VERSION 5.7 ;
BUSBITCHARS "[]" ;
DIVIDERCHAR "/" ;

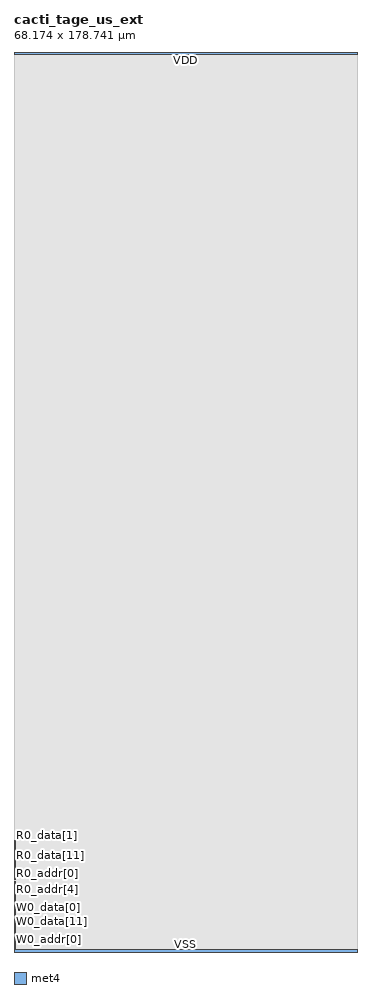
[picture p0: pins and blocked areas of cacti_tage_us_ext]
MACRO cacti_tage_us_ext
  CLASS BLOCK BLACKBOX ;
  ORIGIN 0 0 ;
  FOREIGN cacti_tage_us_ext 0 0 ;
  SIZE 68.174 BY 178.741 ;
  SYMMETRY X Y ;

  PIN VDD
    DIRECTION INOUT ;
    USE POWER ;
    PORT
      LAYER met4 ;
        RECT 0.000 178.241 68.174 178.741 ;
    END
  END VDD
  PIN VSS
    DIRECTION INOUT ;
    USE GROUND ;
    PORT
      LAYER met4 ;
        RECT 0.000 0.000 68.174 0.500 ;
    END
  END VSS
  PIN W0_clk
    DIRECTION INPUT ;
    USE CLOCK ;
    PORT
      LAYER met4 ;
        RECT 0.000 0.700 0.200 0.900 ;
    END
  END W0_clk
  PIN W0_en
    DIRECTION INPUT ;
    USE SIGNAL ;
    PORT
      LAYER met4 ;
        RECT 0.000 1.100 0.200 1.300 ;
    END
  END W0_en
  PIN W0_addr[6]
    DIRECTION INPUT ;
    USE SIGNAL ;
    PORT
      LAYER met4 ;
        RECT 0.000 1.500 0.200 1.700 ;
    END
  END W0_addr[6]
  PIN W0_addr[5]
    DIRECTION INPUT ;
    USE SIGNAL ;
    PORT
      LAYER met4 ;
        RECT 0.000 1.900 0.200 2.100 ;
    END
  END W0_addr[5]
  PIN W0_addr[4]
    DIRECTION INPUT ;
    USE SIGNAL ;
    PORT
      LAYER met4 ;
        RECT 0.000 2.300 0.200 2.500 ;
    END
  END W0_addr[4]
  PIN W0_addr[3]
    DIRECTION INPUT ;
    USE SIGNAL ;
    PORT
      LAYER met4 ;
        RECT 0.000 2.700 0.200 2.900 ;
    END
  END W0_addr[3]
  PIN W0_addr[2]
    DIRECTION INPUT ;
    USE SIGNAL ;
    PORT
      LAYER met4 ;
        RECT 0.000 3.100 0.200 3.300 ;
    END
  END W0_addr[2]
  PIN W0_addr[1]
    DIRECTION INPUT ;
    USE SIGNAL ;
    PORT
      LAYER met4 ;
        RECT 0.000 3.500 0.200 3.700 ;
    END
  END W0_addr[1]
  PIN W0_addr[0]
    DIRECTION INPUT ;
    USE SIGNAL ;
    PORT
      LAYER met4 ;
        RECT 0.000 3.900 0.200 4.100 ;
    END
  END W0_addr[0]
  PIN W0_data[15]
    DIRECTION INPUT ;
    USE SIGNAL ;
    PORT
      LAYER met4 ;
        RECT 0.000 4.300 0.200 4.500 ;
    END
  END W0_data[15]
  PIN W0_data[14]
    DIRECTION INPUT ;
    USE SIGNAL ;
    PORT
      LAYER met4 ;
        RECT 0.000 4.700 0.200 4.900 ;
    END
  END W0_data[14]
  PIN W0_data[13]
    DIRECTION INPUT ;
    USE SIGNAL ;
    PORT
      LAYER met4 ;
        RECT 0.000 5.100 0.200 5.300 ;
    END
  END W0_data[13]
  PIN W0_data[12]
    DIRECTION INPUT ;
    USE SIGNAL ;
    PORT
      LAYER met4 ;
        RECT 0.000 5.500 0.200 5.700 ;
    END
  END W0_data[12]
  PIN W0_data[11]
    DIRECTION INPUT ;
    USE SIGNAL ;
    PORT
      LAYER met4 ;
        RECT 0.000 5.900 0.200 6.100 ;
    END
  END W0_data[11]
  PIN W0_data[10]
    DIRECTION INPUT ;
    USE SIGNAL ;
    PORT
      LAYER met4 ;
        RECT 0.000 6.300 0.200 6.500 ;
    END
  END W0_data[10]
  PIN W0_data[9]
    DIRECTION INPUT ;
    USE SIGNAL ;
    PORT
      LAYER met4 ;
        RECT 0.000 6.700 0.200 6.900 ;
    END
  END W0_data[9]
  PIN W0_data[8]
    DIRECTION INPUT ;
    USE SIGNAL ;
    PORT
      LAYER met4 ;
        RECT 0.000 7.100 0.200 7.300 ;
    END
  END W0_data[8]
  PIN W0_data[7]
    DIRECTION INPUT ;
    USE SIGNAL ;
    PORT
      LAYER met4 ;
        RECT 0.000 7.500 0.200 7.700 ;
    END
  END W0_data[7]
  PIN W0_data[6]
    DIRECTION INPUT ;
    USE SIGNAL ;
    PORT
      LAYER met4 ;
        RECT 0.000 7.900 0.200 8.100 ;
    END
  END W0_data[6]
  PIN W0_data[5]
    DIRECTION INPUT ;
    USE SIGNAL ;
    PORT
      LAYER met4 ;
        RECT 0.000 8.300 0.200 8.500 ;
    END
  END W0_data[5]
  PIN W0_data[4]
    DIRECTION INPUT ;
    USE SIGNAL ;
    PORT
      LAYER met4 ;
        RECT 0.000 8.700 0.200 8.900 ;
    END
  END W0_data[4]
  PIN W0_data[3]
    DIRECTION INPUT ;
    USE SIGNAL ;
    PORT
      LAYER met4 ;
        RECT 0.000 9.100 0.200 9.300 ;
    END
  END W0_data[3]
  PIN W0_data[2]
    DIRECTION INPUT ;
    USE SIGNAL ;
    PORT
      LAYER met4 ;
        RECT 0.000 9.500 0.200 9.700 ;
    END
  END W0_data[2]
  PIN W0_data[1]
    DIRECTION INPUT ;
    USE SIGNAL ;
    PORT
      LAYER met4 ;
        RECT 0.000 9.900 0.200 10.100 ;
    END
  END W0_data[1]
  PIN W0_data[0]
    DIRECTION INPUT ;
    USE SIGNAL ;
    PORT
      LAYER met4 ;
        RECT 0.000 10.300 0.200 10.500 ;
    END
  END W0_data[0]
  PIN W0_mask[3]
    DIRECTION INPUT ;
    USE SIGNAL ;
    PORT
      LAYER met4 ;
        RECT 0.000 10.700 0.200 10.900 ;
    END
  END W0_mask[3]
  PIN W0_mask[2]
    DIRECTION INPUT ;
    USE SIGNAL ;
    PORT
      LAYER met4 ;
        RECT 0.000 11.100 0.200 11.300 ;
    END
  END W0_mask[2]
  PIN W0_mask[1]
    DIRECTION INPUT ;
    USE SIGNAL ;
    PORT
      LAYER met4 ;
        RECT 0.000 11.500 0.200 11.700 ;
    END
  END W0_mask[1]
  PIN W0_mask[0]
    DIRECTION INPUT ;
    USE SIGNAL ;
    PORT
      LAYER met4 ;
        RECT 0.000 11.900 0.200 12.100 ;
    END
  END W0_mask[0]
  PIN R0_clk
    DIRECTION INPUT ;
    USE CLOCK ;
    PORT
      LAYER met4 ;
        RECT 0.000 12.300 0.200 12.500 ;
    END
  END R0_clk
  PIN R0_en
    DIRECTION INPUT ;
    USE SIGNAL ;
    PORT
      LAYER met4 ;
        RECT 0.000 12.700 0.200 12.900 ;
    END
  END R0_en
  PIN R0_addr[6]
    DIRECTION INPUT ;
    USE SIGNAL ;
    PORT
      LAYER met4 ;
        RECT 0.000 13.100 0.200 13.300 ;
    END
  END R0_addr[6]
  PIN R0_addr[5]
    DIRECTION INPUT ;
    USE SIGNAL ;
    PORT
      LAYER met4 ;
        RECT 0.000 13.500 0.200 13.700 ;
    END
  END R0_addr[5]
  PIN R0_addr[4]
    DIRECTION INPUT ;
    USE SIGNAL ;
    PORT
      LAYER met4 ;
        RECT 0.000 13.900 0.200 14.100 ;
    END
  END R0_addr[4]
  PIN R0_addr[3]
    DIRECTION INPUT ;
    USE SIGNAL ;
    PORT
      LAYER met4 ;
        RECT 0.000 14.300 0.200 14.500 ;
    END
  END R0_addr[3]
  PIN R0_addr[2]
    DIRECTION INPUT ;
    USE SIGNAL ;
    PORT
      LAYER met4 ;
        RECT 0.000 14.700 0.200 14.900 ;
    END
  END R0_addr[2]
  PIN R0_addr[1]
    DIRECTION INPUT ;
    USE SIGNAL ;
    PORT
      LAYER met4 ;
        RECT 0.000 15.100 0.200 15.300 ;
    END
  END R0_addr[1]
  PIN R0_addr[0]
    DIRECTION INPUT ;
    USE SIGNAL ;
    PORT
      LAYER met4 ;
        RECT 0.000 15.500 0.200 15.700 ;
    END
  END R0_addr[0]
  PIN R0_data[15]
    DIRECTION OUTPUT ;
    USE SIGNAL ;
    PORT
      LAYER met4 ;
        RECT 0.000 15.900 0.200 16.100 ;
    END
  END R0_data[15]
  PIN R0_data[14]
    DIRECTION OUTPUT ;
    USE SIGNAL ;
    PORT
      LAYER met4 ;
        RECT 0.000 16.300 0.200 16.500 ;
    END
  END R0_data[14]
  PIN R0_data[13]
    DIRECTION OUTPUT ;
    USE SIGNAL ;
    PORT
      LAYER met4 ;
        RECT 0.000 16.700 0.200 16.900 ;
    END
  END R0_data[13]
  PIN R0_data[12]
    DIRECTION OUTPUT ;
    USE SIGNAL ;
    PORT
      LAYER met4 ;
        RECT 0.000 17.100 0.200 17.300 ;
    END
  END R0_data[12]
  PIN R0_data[11]
    DIRECTION OUTPUT ;
    USE SIGNAL ;
    PORT
      LAYER met4 ;
        RECT 0.000 17.500 0.200 17.700 ;
    END
  END R0_data[11]
  PIN R0_data[10]
    DIRECTION OUTPUT ;
    USE SIGNAL ;
    PORT
      LAYER met4 ;
        RECT 0.000 17.900 0.200 18.100 ;
    END
  END R0_data[10]
  PIN R0_data[9]
    DIRECTION OUTPUT ;
    USE SIGNAL ;
    PORT
      LAYER met4 ;
        RECT 0.000 18.300 0.200 18.500 ;
    END
  END R0_data[9]
  PIN R0_data[8]
    DIRECTION OUTPUT ;
    USE SIGNAL ;
    PORT
      LAYER met4 ;
        RECT 0.000 18.700 0.200 18.900 ;
    END
  END R0_data[8]
  PIN R0_data[7]
    DIRECTION OUTPUT ;
    USE SIGNAL ;
    PORT
      LAYER met4 ;
        RECT 0.000 19.100 0.200 19.300 ;
    END
  END R0_data[7]
  PIN R0_data[6]
    DIRECTION OUTPUT ;
    USE SIGNAL ;
    PORT
      LAYER met4 ;
        RECT 0.000 19.500 0.200 19.700 ;
    END
  END R0_data[6]
  PIN R0_data[5]
    DIRECTION OUTPUT ;
    USE SIGNAL ;
    PORT
      LAYER met4 ;
        RECT 0.000 19.900 0.200 20.100 ;
    END
  END R0_data[5]
  PIN R0_data[4]
    DIRECTION OUTPUT ;
    USE SIGNAL ;
    PORT
      LAYER met4 ;
        RECT 0.000 20.300 0.200 20.500 ;
    END
  END R0_data[4]
  PIN R0_data[3]
    DIRECTION OUTPUT ;
    USE SIGNAL ;
    PORT
      LAYER met4 ;
        RECT 0.000 20.700 0.200 20.900 ;
    END
  END R0_data[3]
  PIN R0_data[2]
    DIRECTION OUTPUT ;
    USE SIGNAL ;
    PORT
      LAYER met4 ;
        RECT 0.000 21.100 0.200 21.300 ;
    END
  END R0_data[2]
  PIN R0_data[1]
    DIRECTION OUTPUT ;
    USE SIGNAL ;
    PORT
      LAYER met4 ;
        RECT 0.000 21.500 0.200 21.700 ;
    END
  END R0_data[1]
  PIN R0_data[0]
    DIRECTION OUTPUT ;
    USE SIGNAL ;
    PORT
      LAYER met4 ;
        RECT 0.000 21.900 0.200 22.100 ;
    END
  END R0_data[0]
  OBS
    LAYER met1 ;
      RECT 0.000 0.000 68.174 178.741 ;
    LAYER met2 ;
      RECT 0.000 0.000 68.174 178.741 ;
    LAYER met3 ;
      RECT 0.000 0.000 68.174 178.741 ;
  END
END cacti_tage_us_ext

END LIBRARY
